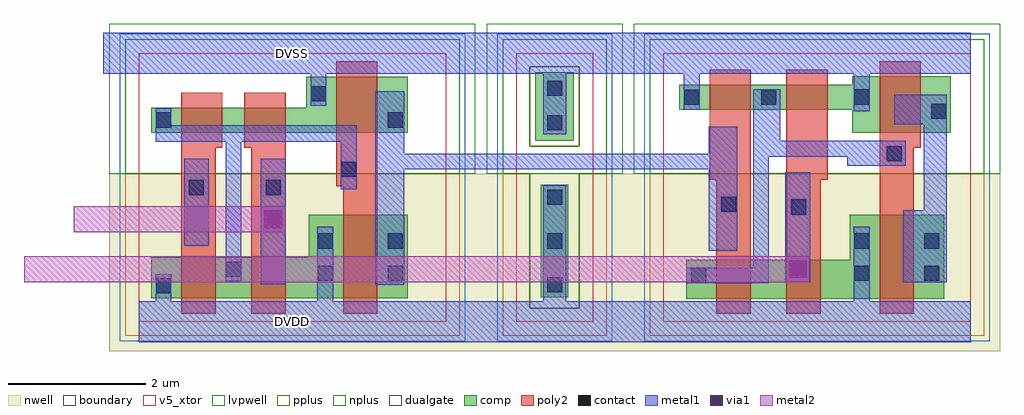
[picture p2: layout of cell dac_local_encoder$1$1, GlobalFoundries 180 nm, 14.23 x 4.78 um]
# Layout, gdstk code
import gdstk
lib = gdstk.Library(unit=1e-6, precision=1e-09)
def R(c, l, rs):  # rectangles x0, y0, x1, y1
    for r in rs: c.add(gdstk.rectangle(r[:2], r[2:], *l))
def A(c, l, x, y, w, h, nx, ny, dx, dy):  # array of equal rectangles
    R(c, l, [(x+i*dx, y+j*dy, x+i*dx+w, y+j*dy+h) for i in range(nx) for j in range(ny)])
def P(c, l, *ps):  # polygons
    for p in ps: c.add(gdstk.Polygon(p, *l))
boundary = (0, 0)
nwell = (21, 0)
comp = (22, 0)
poly2 = (30, 0)
pplus = (31, 0)
nplus = (32, 0)
contact = (33, 0)
metal1 = (34, 0)
via1 = (35, 0)
metal2 = (36, 0)
dualgate = (55, 0)
v5_xtor = (112, 1)
lvpwell = (204, 0)

dac_local_encoder_1_1 = lib.new_cell('dac_local_encoder$1$1')
R(dac_local_encoder_1_1, boundary, [(-5.44,0.29,-0.96,4.21), (0.065,0.29,1.185,4.21), (2.21,0.29,6.69,4.21)])
R(dac_local_encoder_1_1, nwell, [(-5.87,-0.14,-0.53,2.45), (-0.53,-0.14,-0.365,2.45), (-0.365,-0.14,1.615,2.45), (1.615,-0.14,1.78,2.45), (1.78,-0.14,7.12,2.45)])
R(dac_local_encoder_1_1, comp, [(0.425,0.65,0.825,2.29), (0.345,2.93,0.905,3.93)])
P(dac_local_encoder_1_1, comp, [(-5.26,3.05),(-5.26,3.415),(-3,3.415),(-3,3.865),(-1.52,3.865),(-1.52,3.05)],
  [(-5.26,0.635),(-5.26,1.235),(-2.96,1.235),(-2.96,1.85),(-1.52,1.85),(-1.52,0.635)],
  [(2.545,0.63),(2.545,1.195),(4.925,1.195),(4.925,1.85),(6.305,1.85),(6.305,0.63)],
  [(4.965,3.05),(4.965,3.385),(2.445,3.385),(2.445,3.745),(4.965,3.745),(4.965,3.87),(6.405,3.87),(6.405,3.05)])
P(dac_local_encoder_1_1, poly2, [(-4.82,0.41),(-4.82,3.635),(-4.22,3.635),(-4.22,2.83),(-4.32,2.83),(-4.32,0.41)],
  [(-3.8,0.41),(-3.8,2.83),(-3.9,2.83),(-3.9,3.635),(-3.3,3.635),(-3.3,0.41)],
  [(-2.46,0.41),(-2.46,2.265),(-2.56,2.265),(-2.56,4.09),(-1.96,4.09),(-1.96,0.41)],
  [(2.985,0.41),(2.985,2.365),(2.885,2.365),(2.885,3.97),(3.485,3.97),(3.485,0.41)],
  [(4.005,0.41),(4.005,3.97),(4.605,3.97),(4.605,2.365),(4.505,2.365),(4.505,0.41)],
  [(5.365,0.41),(5.365,4.09),(5.965,4.09),(5.965,2.83),(5.865,2.83),(5.865,0.41)])
R(dac_local_encoder_1_1, pplus, [(-5.64,0.09,-0.76,2.45), (2.01,0.09,6.89,2.45), (0.265,2.85,0.985,4.01)])
P(dac_local_encoder_1_1, pplus, [(-0.135,0.09),(-0.135,2.45),(0.265,2.45),(0.265,0.49),(0.985,0.49),(0.985,2.45),(1.385,2.45),(1.385,0.09)])
R(dac_local_encoder_1_1, nplus, [(-5.64,2.45,-0.76,4.41), (2.01,2.45,6.89,4.41)])
P(dac_local_encoder_1_1, nplus, [(0.265,0.49),(0.265,2.45),(-0.135,2.45),(-0.135,4.41),(1.385,4.41),(1.385,2.45),(0.985,2.45),(0.985,0.49),(0.985,4.01),(0.265,4.01),(0.265,2.85),(0.985,2.85),(0.985,0.49)])
A(dac_local_encoder_1_1, contact, 0.515, 0.72, 0.22, 0.22, 1, 3, 0, 0.64)
R(dac_local_encoder_1_1, contact, [(-5.19,0.705,-4.97,0.925), (2.615,0.855,2.835,1.075), (-2.83,0.89,-2.61,1.11), (-1.81,0.89,-1.59,1.11), (4.995,0.89,5.215,1.11), (6.015,0.89,6.235,1.11), (-4.17,0.945,-3.95,1.165), (-2.83,1.36,-2.61,1.58), (-1.81,1.36,-1.59,1.58), (4.995,1.36,5.215,1.58), (6.015,1.36,6.235,1.58), (4.075,1.855,4.295,2.075), (3.055,1.895,3.275,2.115), (-4.71,2.14,-4.49,2.36), (-3.59,2.14,-3.37,2.36), (-2.49,2.405,-2.27,2.625), (5.465,2.63,5.685,2.85), (0.515,3.085,0.735,3.305), (-5.19,3.125,-4.97,3.345), (-1.81,3.125,-1.59,3.345), (6.115,3.255,6.335,3.475), (2.515,3.455,2.735,3.675), (3.635,3.455,3.855,3.675), (4.995,3.46,5.215,3.68), (-2.93,3.505,-2.71,3.725), (0.515,3.59,0.735,3.81)])
R(dac_local_encoder_1_1, metal1, [(-5.44,-0.01,6.69,0.59), (-1.99,0.83,-1.57,3.655), (-3.66,0.84,-3.3,2.67), (3.99,0.865,4.35,2.47), (2.87,1.33,3.29,3.135), (-4.78,1.4,-4.42,2.67), (-1.96,2.515,3.29,2.745), (-5.96,3.91,6.17,4.51)])
P(dac_local_encoder_1_1, metal1, [(2.545,0.85),(2.545,1.08),(3.52,1.08),(3.52,3.68),(3.915,3.68),(3.915,2.93),(5.745,2.93),(5.745,2.57),(4.89,2.57),(4.89,2.7),(3.75,2.7),(3.75,0.85)],
  [(5.71,0.865),(5.71,1.92),(6.01,1.92),(6.01,3.17),(5.575,3.17),(5.575,3.6),(6.34,3.6),(6.34,0.865)],
  [(4.99,3.36),(4.99,3.91),(2.74,3.91),(2.74,3.385),(2.51,3.385),(2.51,3.91),(2.21,3.91),(2.21,4.51),(6.69,4.51),(6.69,3.91),(5.22,3.91),(5.22,3.36)],
  [(2.21,-0.01),(2.21,0.59),(4.99,0.59),(4.99,1.68),(5.22,1.68),(5.22,0.59),(6.69,0.59),(6.69,-0.01)],
  [(0.455,3.025),(0.455,3.91),(0.065,3.91),(0.065,4.51),(1.185,4.51),(1.185,3.91),(0.795,3.91),(0.795,3.025)],
  [(0.065,-0.01),(0.065,0.59),(0.455,0.59),(0.455,2.28),(0.795,2.28),(0.795,0.59),(1.185,0.59),(1.185,-0.01)],
  [(-4.175,0.885),(-4.175,2.92),(-5.195,2.92),(-5.195,3.405),(-4.965,3.405),(-4.965,3.155),(-2.265,3.155),(-2.265,2.225),(-2.495,2.225),(-2.495,2.92),(-3.945,2.92),(-3.945,0.885)],
  [(-2.935,3.445),(-2.935,3.91),(-5.44,3.91),(-5.44,4.51),(-0.96,4.51),(-0.96,3.91),(-2.705,3.91),(-2.705,3.445)],
  [(-5.44,-0.01),(-5.44,0.59),(-5.195,0.59),(-5.195,0.985),(-4.965,0.985),(-4.965,0.59),(-2.835,0.59),(-2.835,1.68),(-2.605,1.68),(-2.605,0.59),(-0.96,0.59),(-0.96,-0.01)])
R(dac_local_encoder_1_1, via1, [(4.04,0.925,4.3,1.185), (-3.61,1.655,-3.35,1.915)])
R(dac_local_encoder_1_1, metal2, [(-7.115,0.865,1.06,1.245), (1.06,0.865,4.345,1.245), (-6.39,1.595,-3.3,1.975)])
R(dac_local_encoder_1_1, dualgate, [(-5.72,0.01,-0.68,4.49), (-0.215,0.01,1.465,4.49), (1.93,0.01,6.97,4.49)])
R(dac_local_encoder_1_1, v5_xtor, [(-5.44,0.29,-0.96,4.21), (0.065,0.29,1.185,4.21), (2.21,0.29,6.69,4.21)])
R(dac_local_encoder_1_1, lvpwell, [(-5.87,2.45,-0.53,4.64), (-0.365,2.45,1.615,4.64), (1.78,2.45,7.12,4.64)])
dac_local_encoder_1_1.add(gdstk.Label('DVDD', (-3.2,0.29), layer=34, texttype=10))
dac_local_encoder_1_1.add(gdstk.Label('DVSS', (-3.2,4.21), layer=34, texttype=10))

lib.write_gds('dac_local_encoder_1_1.gds')
